VERSION 5.7 ;
BUSBITCHARS "[]" ;
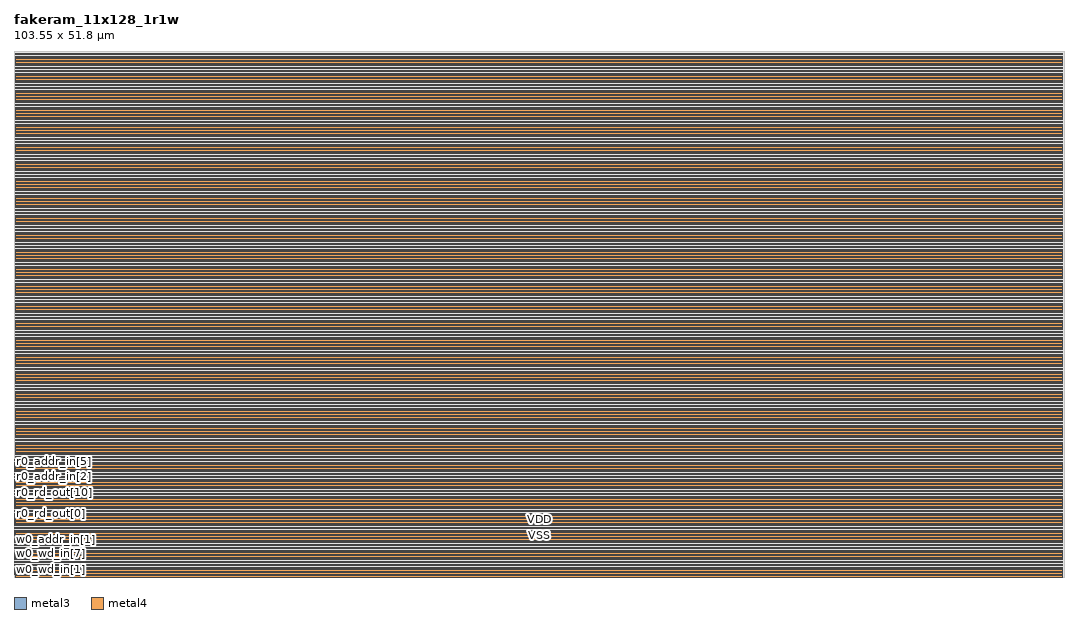
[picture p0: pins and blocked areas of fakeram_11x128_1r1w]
MACRO fakeram_11x128_1r1w
  FOREIGN fakeram_11x128_1r1w 0 0 ;
  SYMMETRY X Y R90 ;
  SIZE 103.550 BY 51.800 ;
  CLASS BLOCK ;
  PIN w0_wd_in[0]
    DIRECTION INPUT ;
    USE SIGNAL ;
    SHAPE ABUTMENT ;
    PORT
      LAYER metal3 ;
      RECT 0.000 0.280 0.140 0.420 ;
    END
  END w0_wd_in[0]
  PIN w0_wd_in[1]
    DIRECTION INPUT ;
    USE SIGNAL ;
    SHAPE ABUTMENT ;
    PORT
      LAYER metal3 ;
      RECT 0.000 0.560 0.140 0.700 ;
    END
  END w0_wd_in[1]
  PIN w0_wd_in[2]
    DIRECTION INPUT ;
    USE SIGNAL ;
    SHAPE ABUTMENT ;
    PORT
      LAYER metal3 ;
      RECT 0.000 0.840 0.140 0.980 ;
    END
  END w0_wd_in[2]
  PIN w0_wd_in[3]
    DIRECTION INPUT ;
    USE SIGNAL ;
    SHAPE ABUTMENT ;
    PORT
      LAYER metal3 ;
      RECT 0.000 1.120 0.140 1.260 ;
    END
  END w0_wd_in[3]
  PIN w0_wd_in[4]
    DIRECTION INPUT ;
    USE SIGNAL ;
    SHAPE ABUTMENT ;
    PORT
      LAYER metal3 ;
      RECT 0.000 1.400 0.140 1.540 ;
    END
  END w0_wd_in[4]
  PIN w0_wd_in[5]
    DIRECTION INPUT ;
    USE SIGNAL ;
    SHAPE ABUTMENT ;
    PORT
      LAYER metal3 ;
      RECT 0.000 1.680 0.140 1.820 ;
    END
  END w0_wd_in[5]
  PIN w0_wd_in[6]
    DIRECTION INPUT ;
    USE SIGNAL ;
    SHAPE ABUTMENT ;
    PORT
      LAYER metal3 ;
      RECT 0.000 1.960 0.140 2.100 ;
    END
  END w0_wd_in[6]
  PIN w0_wd_in[7]
    DIRECTION INPUT ;
    USE SIGNAL ;
    SHAPE ABUTMENT ;
    PORT
      LAYER metal3 ;
      RECT 0.000 2.240 0.140 2.380 ;
    END
  END w0_wd_in[7]
  PIN w0_wd_in[8]
    DIRECTION INPUT ;
    USE SIGNAL ;
    SHAPE ABUTMENT ;
    PORT
      LAYER metal3 ;
      RECT 0.000 2.520 0.140 2.660 ;
    END
  END w0_wd_in[8]
  PIN w0_wd_in[9]
    DIRECTION INPUT ;
    USE SIGNAL ;
    SHAPE ABUTMENT ;
    PORT
      LAYER metal3 ;
      RECT 0.000 2.800 0.140 2.940 ;
    END
  END w0_wd_in[9]
  PIN w0_wd_in[10]
    DIRECTION INPUT ;
    USE SIGNAL ;
    SHAPE ABUTMENT ;
    PORT
      LAYER metal3 ;
      RECT 0.000 3.080 0.140 3.220 ;
    END
  END w0_wd_in[10]
  PIN w0_addr_in[0]
    DIRECTION INPUT ;
    USE SIGNAL ;
    SHAPE ABUTMENT ;
    PORT
      LAYER metal3 ;
      RECT 0.000 3.360 0.140 3.500 ;
    END
  END w0_addr_in[0]
  PIN w0_addr_in[1]
    DIRECTION INPUT ;
    USE SIGNAL ;
    SHAPE ABUTMENT ;
    PORT
      LAYER metal3 ;
      RECT 0.000 3.640 0.140 3.780 ;
    END
  END w0_addr_in[1]
  PIN w0_addr_in[2]
    DIRECTION INPUT ;
    USE SIGNAL ;
    SHAPE ABUTMENT ;
    PORT
      LAYER metal3 ;
      RECT 0.000 3.920 0.140 4.060 ;
    END
  END w0_addr_in[2]
  PIN w0_addr_in[3]
    DIRECTION INPUT ;
    USE SIGNAL ;
    SHAPE ABUTMENT ;
    PORT
      LAYER metal3 ;
      RECT 0.000 4.200 0.140 4.340 ;
    END
  END w0_addr_in[3]
  PIN w0_addr_in[4]
    DIRECTION INPUT ;
    USE SIGNAL ;
    SHAPE ABUTMENT ;
    PORT
      LAYER metal3 ;
      RECT 0.000 4.480 0.140 4.620 ;
    END
  END w0_addr_in[4]
  PIN w0_addr_in[5]
    DIRECTION INPUT ;
    USE SIGNAL ;
    SHAPE ABUTMENT ;
    PORT
      LAYER metal3 ;
      RECT 0.000 4.760 0.140 4.900 ;
    END
  END w0_addr_in[5]
  PIN w0_addr_in[6]
    DIRECTION INPUT ;
    USE SIGNAL ;
    SHAPE ABUTMENT ;
    PORT
      LAYER metal3 ;
      RECT 0.000 5.040 0.140 5.180 ;
    END
  END w0_addr_in[6]
  PIN w0_clk
    DIRECTION INPUT ;
    USE SIGNAL ;
    SHAPE ABUTMENT ;
    PORT
      LAYER metal3 ;
      RECT 0.000 5.320 0.140 5.460 ;
    END
  END w0_clk
  PIN w0_ce_in
    DIRECTION INPUT ;
    USE SIGNAL ;
    SHAPE ABUTMENT ;
    PORT
      LAYER metal3 ;
      RECT 0.000 5.600 0.140 5.740 ;
    END
  END w0_ce_in
  PIN w0_we_in
    DIRECTION INPUT ;
    USE SIGNAL ;
    SHAPE ABUTMENT ;
    PORT
      LAYER metal3 ;
      RECT 0.000 5.880 0.140 6.020 ;
    END
  END w0_we_in
  PIN r0_rd_out[0]
    DIRECTION OUTPUT ;
    USE SIGNAL ;
    SHAPE ABUTMENT ;
    PORT
      LAYER metal3 ;
      RECT 0.000 6.160 0.140 6.300 ;
    END
  END r0_rd_out[0]
  PIN r0_rd_out[1]
    DIRECTION OUTPUT ;
    USE SIGNAL ;
    SHAPE ABUTMENT ;
    PORT
      LAYER metal3 ;
      RECT 0.000 6.440 0.140 6.580 ;
    END
  END r0_rd_out[1]
  PIN r0_rd_out[2]
    DIRECTION OUTPUT ;
    USE SIGNAL ;
    SHAPE ABUTMENT ;
    PORT
      LAYER metal3 ;
      RECT 0.000 6.720 0.140 6.860 ;
    END
  END r0_rd_out[2]
  PIN r0_rd_out[3]
    DIRECTION OUTPUT ;
    USE SIGNAL ;
    SHAPE ABUTMENT ;
    PORT
      LAYER metal3 ;
      RECT 0.000 7.000 0.140 7.140 ;
    END
  END r0_rd_out[3]
  PIN r0_rd_out[4]
    DIRECTION OUTPUT ;
    USE SIGNAL ;
    SHAPE ABUTMENT ;
    PORT
      LAYER metal3 ;
      RECT 0.000 7.280 0.140 7.420 ;
    END
  END r0_rd_out[4]
  PIN r0_rd_out[5]
    DIRECTION OUTPUT ;
    USE SIGNAL ;
    SHAPE ABUTMENT ;
    PORT
      LAYER metal3 ;
      RECT 0.000 7.560 0.140 7.700 ;
    END
  END r0_rd_out[5]
  PIN r0_rd_out[6]
    DIRECTION OUTPUT ;
    USE SIGNAL ;
    SHAPE ABUTMENT ;
    PORT
      LAYER metal3 ;
      RECT 0.000 7.840 0.140 7.980 ;
    END
  END r0_rd_out[6]
  PIN r0_rd_out[7]
    DIRECTION OUTPUT ;
    USE SIGNAL ;
    SHAPE ABUTMENT ;
    PORT
      LAYER metal3 ;
      RECT 0.000 8.120 0.140 8.260 ;
    END
  END r0_rd_out[7]
  PIN r0_rd_out[8]
    DIRECTION OUTPUT ;
    USE SIGNAL ;
    SHAPE ABUTMENT ;
    PORT
      LAYER metal3 ;
      RECT 0.000 8.400 0.140 8.540 ;
    END
  END r0_rd_out[8]
  PIN r0_rd_out[9]
    DIRECTION OUTPUT ;
    USE SIGNAL ;
    SHAPE ABUTMENT ;
    PORT
      LAYER metal3 ;
      RECT 0.000 8.680 0.140 8.820 ;
    END
  END r0_rd_out[9]
  PIN r0_rd_out[10]
    DIRECTION OUTPUT ;
    USE SIGNAL ;
    SHAPE ABUTMENT ;
    PORT
      LAYER metal3 ;
      RECT 0.000 8.960 0.140 9.100 ;
    END
  END r0_rd_out[10]
  PIN r0_addr_in[0]
    DIRECTION INPUT ;
    USE SIGNAL ;
    SHAPE ABUTMENT ;
    PORT
      LAYER metal3 ;
      RECT 0.000 9.240 0.140 9.380 ;
    END
  END r0_addr_in[0]
  PIN r0_addr_in[1]
    DIRECTION INPUT ;
    USE SIGNAL ;
    SHAPE ABUTMENT ;
    PORT
      LAYER metal3 ;
      RECT 0.000 9.520 0.140 9.660 ;
    END
  END r0_addr_in[1]
  PIN r0_addr_in[2]
    DIRECTION INPUT ;
    USE SIGNAL ;
    SHAPE ABUTMENT ;
    PORT
      LAYER metal3 ;
      RECT 0.000 9.800 0.140 9.940 ;
    END
  END r0_addr_in[2]
  PIN r0_addr_in[3]
    DIRECTION INPUT ;
    USE SIGNAL ;
    SHAPE ABUTMENT ;
    PORT
      LAYER metal3 ;
      RECT 0.000 10.080 0.140 10.220 ;
    END
  END r0_addr_in[3]
  PIN r0_addr_in[4]
    DIRECTION INPUT ;
    USE SIGNAL ;
    SHAPE ABUTMENT ;
    PORT
      LAYER metal3 ;
      RECT 0.000 10.360 0.140 10.500 ;
    END
  END r0_addr_in[4]
  PIN r0_addr_in[5]
    DIRECTION INPUT ;
    USE SIGNAL ;
    SHAPE ABUTMENT ;
    PORT
      LAYER metal3 ;
      RECT 0.000 10.640 0.140 10.780 ;
    END
  END r0_addr_in[5]
  PIN r0_addr_in[6]
    DIRECTION INPUT ;
    USE SIGNAL ;
    SHAPE ABUTMENT ;
    PORT
      LAYER metal3 ;
      RECT 0.000 10.920 0.140 11.060 ;
    END
  END r0_addr_in[6]
  PIN r0_clk
    DIRECTION INPUT ;
    USE SIGNAL ;
    SHAPE ABUTMENT ;
    PORT
      LAYER metal3 ;
      RECT 0.000 11.200 0.140 11.340 ;
    END
  END r0_clk
  PIN r0_ce_in
    DIRECTION INPUT ;
    USE SIGNAL ;
    SHAPE ABUTMENT ;
    PORT
      LAYER metal3 ;
      RECT 0.000 11.480 0.140 11.620 ;
    END
  END r0_ce_in
  PIN VDD
    DIRECTION INOUT ;
    USE POWER ;
    PORT
      LAYER metal4 ;
      RECT 0.190 0.000 103.360 0.140 ;
      RECT 0.190 0.560 103.360 0.700 ;
      RECT 0.190 1.120 103.360 1.260 ;
      RECT 0.190 1.680 103.360 1.820 ;
      RECT 0.190 2.240 103.360 2.380 ;
      RECT 0.190 2.800 103.360 2.940 ;
      RECT 0.190 3.360 103.360 3.500 ;
      RECT 0.190 3.920 103.360 4.060 ;
      RECT 0.190 4.480 103.360 4.620 ;
      RECT 0.190 5.040 103.360 5.180 ;
      RECT 0.190 5.600 103.360 5.740 ;
      RECT 0.190 6.160 103.360 6.300 ;
      RECT 0.190 6.720 103.360 6.860 ;
      RECT 0.190 7.280 103.360 7.420 ;
      RECT 0.190 7.840 103.360 7.980 ;
      RECT 0.190 8.400 103.360 8.540 ;
      RECT 0.190 8.960 103.360 9.100 ;
      RECT 0.190 9.520 103.360 9.660 ;
      RECT 0.190 10.080 103.360 10.220 ;
      RECT 0.190 10.640 103.360 10.780 ;
      RECT 0.190 11.200 103.360 11.340 ;
      RECT 0.190 11.760 103.360 11.900 ;
      RECT 0.190 12.320 103.360 12.460 ;
      RECT 0.190 12.880 103.360 13.020 ;
      RECT 0.190 13.440 103.360 13.580 ;
      RECT 0.190 14.000 103.360 14.140 ;
      RECT 0.190 14.560 103.360 14.700 ;
      RECT 0.190 15.120 103.360 15.260 ;
      RECT 0.190 15.680 103.360 15.820 ;
      RECT 0.190 16.240 103.360 16.380 ;
      RECT 0.190 16.800 103.360 16.940 ;
      RECT 0.190 17.360 103.360 17.500 ;
      RECT 0.190 17.920 103.360 18.060 ;
      RECT 0.190 18.480 103.360 18.620 ;
      RECT 0.190 19.040 103.360 19.180 ;
      RECT 0.190 19.600 103.360 19.740 ;
      RECT 0.190 20.160 103.360 20.300 ;
      RECT 0.190 20.720 103.360 20.860 ;
      RECT 0.190 21.280 103.360 21.420 ;
      RECT 0.190 21.840 103.360 21.980 ;
      RECT 0.190 22.400 103.360 22.540 ;
      RECT 0.190 22.960 103.360 23.100 ;
      RECT 0.190 23.520 103.360 23.660 ;
      RECT 0.190 24.080 103.360 24.220 ;
      RECT 0.190 24.640 103.360 24.780 ;
      RECT 0.190 25.200 103.360 25.340 ;
      RECT 0.190 25.760 103.360 25.900 ;
      RECT 0.190 26.320 103.360 26.460 ;
      RECT 0.190 26.880 103.360 27.020 ;
      RECT 0.190 27.440 103.360 27.580 ;
      RECT 0.190 28.000 103.360 28.140 ;
      RECT 0.190 28.560 103.360 28.700 ;
      RECT 0.190 29.120 103.360 29.260 ;
      RECT 0.190 29.680 103.360 29.820 ;
      RECT 0.190 30.240 103.360 30.380 ;
      RECT 0.190 30.800 103.360 30.940 ;
      RECT 0.190 31.360 103.360 31.500 ;
      RECT 0.190 31.920 103.360 32.060 ;
      RECT 0.190 32.480 103.360 32.620 ;
      RECT 0.190 33.040 103.360 33.180 ;
      RECT 0.190 33.600 103.360 33.740 ;
      RECT 0.190 34.160 103.360 34.300 ;
      RECT 0.190 34.720 103.360 34.860 ;
      RECT 0.190 35.280 103.360 35.420 ;
      RECT 0.190 35.840 103.360 35.980 ;
      RECT 0.190 36.400 103.360 36.540 ;
      RECT 0.190 36.960 103.360 37.100 ;
      RECT 0.190 37.520 103.360 37.660 ;
      RECT 0.190 38.080 103.360 38.220 ;
      RECT 0.190 38.640 103.360 38.780 ;
      RECT 0.190 39.200 103.360 39.340 ;
      RECT 0.190 39.760 103.360 39.900 ;
      RECT 0.190 40.320 103.360 40.460 ;
      RECT 0.190 40.880 103.360 41.020 ;
      RECT 0.190 41.440 103.360 41.580 ;
      RECT 0.190 42.000 103.360 42.140 ;
      RECT 0.190 42.560 103.360 42.700 ;
      RECT 0.190 43.120 103.360 43.260 ;
      RECT 0.190 43.680 103.360 43.820 ;
      RECT 0.190 44.240 103.360 44.380 ;
      RECT 0.190 44.800 103.360 44.940 ;
      RECT 0.190 45.360 103.360 45.500 ;
      RECT 0.190 45.920 103.360 46.060 ;
      RECT 0.190 46.480 103.360 46.620 ;
      RECT 0.190 47.040 103.360 47.180 ;
      RECT 0.190 47.600 103.360 47.740 ;
      RECT 0.190 48.160 103.360 48.300 ;
      RECT 0.190 48.720 103.360 48.860 ;
      RECT 0.190 49.280 103.360 49.420 ;
      RECT 0.190 49.840 103.360 49.980 ;
      RECT 0.190 50.400 103.360 50.540 ;
      RECT 0.190 50.960 103.360 51.100 ;
      RECT 0.190 51.520 103.360 51.660 ;
    END
  END VDD
  PIN VSS
    DIRECTION INOUT ;
    USE GROUND ;
    PORT
      LAYER metal4 ;
      RECT 0.190 0.280 103.360 0.420 ;
      RECT 0.190 0.840 103.360 0.980 ;
      RECT 0.190 1.400 103.360 1.540 ;
      RECT 0.190 1.960 103.360 2.100 ;
      RECT 0.190 2.520 103.360 2.660 ;
      RECT 0.190 3.080 103.360 3.220 ;
      RECT 0.190 3.640 103.360 3.780 ;
      RECT 0.190 4.200 103.360 4.340 ;
      RECT 0.190 4.760 103.360 4.900 ;
      RECT 0.190 5.320 103.360 5.460 ;
      RECT 0.190 5.880 103.360 6.020 ;
      RECT 0.190 6.440 103.360 6.580 ;
      RECT 0.190 7.000 103.360 7.140 ;
      RECT 0.190 7.560 103.360 7.700 ;
      RECT 0.190 8.120 103.360 8.260 ;
      RECT 0.190 8.680 103.360 8.820 ;
      RECT 0.190 9.240 103.360 9.380 ;
      RECT 0.190 9.800 103.360 9.940 ;
      RECT 0.190 10.360 103.360 10.500 ;
      RECT 0.190 10.920 103.360 11.060 ;
      RECT 0.190 11.480 103.360 11.620 ;
      RECT 0.190 12.040 103.360 12.180 ;
      RECT 0.190 12.600 103.360 12.740 ;
      RECT 0.190 13.160 103.360 13.300 ;
      RECT 0.190 13.720 103.360 13.860 ;
      RECT 0.190 14.280 103.360 14.420 ;
      RECT 0.190 14.840 103.360 14.980 ;
      RECT 0.190 15.400 103.360 15.540 ;
      RECT 0.190 15.960 103.360 16.100 ;
      RECT 0.190 16.520 103.360 16.660 ;
      RECT 0.190 17.080 103.360 17.220 ;
      RECT 0.190 17.640 103.360 17.780 ;
      RECT 0.190 18.200 103.360 18.340 ;
      RECT 0.190 18.760 103.360 18.900 ;
      RECT 0.190 19.320 103.360 19.460 ;
      RECT 0.190 19.880 103.360 20.020 ;
      RECT 0.190 20.440 103.360 20.580 ;
      RECT 0.190 21.000 103.360 21.140 ;
      RECT 0.190 21.560 103.360 21.700 ;
      RECT 0.190 22.120 103.360 22.260 ;
      RECT 0.190 22.680 103.360 22.820 ;
      RECT 0.190 23.240 103.360 23.380 ;
      RECT 0.190 23.800 103.360 23.940 ;
      RECT 0.190 24.360 103.360 24.500 ;
      RECT 0.190 24.920 103.360 25.060 ;
      RECT 0.190 25.480 103.360 25.620 ;
      RECT 0.190 26.040 103.360 26.180 ;
      RECT 0.190 26.600 103.360 26.740 ;
      RECT 0.190 27.160 103.360 27.300 ;
      RECT 0.190 27.720 103.360 27.860 ;
      RECT 0.190 28.280 103.360 28.420 ;
      RECT 0.190 28.840 103.360 28.980 ;
      RECT 0.190 29.400 103.360 29.540 ;
      RECT 0.190 29.960 103.360 30.100 ;
      RECT 0.190 30.520 103.360 30.660 ;
      RECT 0.190 31.080 103.360 31.220 ;
      RECT 0.190 31.640 103.360 31.780 ;
      RECT 0.190 32.200 103.360 32.340 ;
      RECT 0.190 32.760 103.360 32.900 ;
      RECT 0.190 33.320 103.360 33.460 ;
      RECT 0.190 33.880 103.360 34.020 ;
      RECT 0.190 34.440 103.360 34.580 ;
      RECT 0.190 35.000 103.360 35.140 ;
      RECT 0.190 35.560 103.360 35.700 ;
      RECT 0.190 36.120 103.360 36.260 ;
      RECT 0.190 36.680 103.360 36.820 ;
      RECT 0.190 37.240 103.360 37.380 ;
      RECT 0.190 37.800 103.360 37.940 ;
      RECT 0.190 38.360 103.360 38.500 ;
      RECT 0.190 38.920 103.360 39.060 ;
      RECT 0.190 39.480 103.360 39.620 ;
      RECT 0.190 40.040 103.360 40.180 ;
      RECT 0.190 40.600 103.360 40.740 ;
      RECT 0.190 41.160 103.360 41.300 ;
      RECT 0.190 41.720 103.360 41.860 ;
      RECT 0.190 42.280 103.360 42.420 ;
      RECT 0.190 42.840 103.360 42.980 ;
      RECT 0.190 43.400 103.360 43.540 ;
      RECT 0.190 43.960 103.360 44.100 ;
      RECT 0.190 44.520 103.360 44.660 ;
      RECT 0.190 45.080 103.360 45.220 ;
      RECT 0.190 45.640 103.360 45.780 ;
      RECT 0.190 46.200 103.360 46.340 ;
      RECT 0.190 46.760 103.360 46.900 ;
      RECT 0.190 47.320 103.360 47.460 ;
      RECT 0.190 47.880 103.360 48.020 ;
      RECT 0.190 48.440 103.360 48.580 ;
      RECT 0.190 49.000 103.360 49.140 ;
      RECT 0.190 49.560 103.360 49.700 ;
      RECT 0.190 50.120 103.360 50.260 ;
      RECT 0.190 50.680 103.360 50.820 ;
      RECT 0.190 51.240 103.360 51.380 ;
    END
  END VSS
  OBS
    LAYER metal1 ;
      RECT 0.000 0.000 103.550 51.800 ;
    LAYER metal2 ;
      RECT 0.000 0.000 103.550 51.800 ;
    LAYER metal3 ;
      RECT 0.000 0.000 103.550 51.800 ;
  END
END fakeram_11x128_1r1w
END LIBRARY
